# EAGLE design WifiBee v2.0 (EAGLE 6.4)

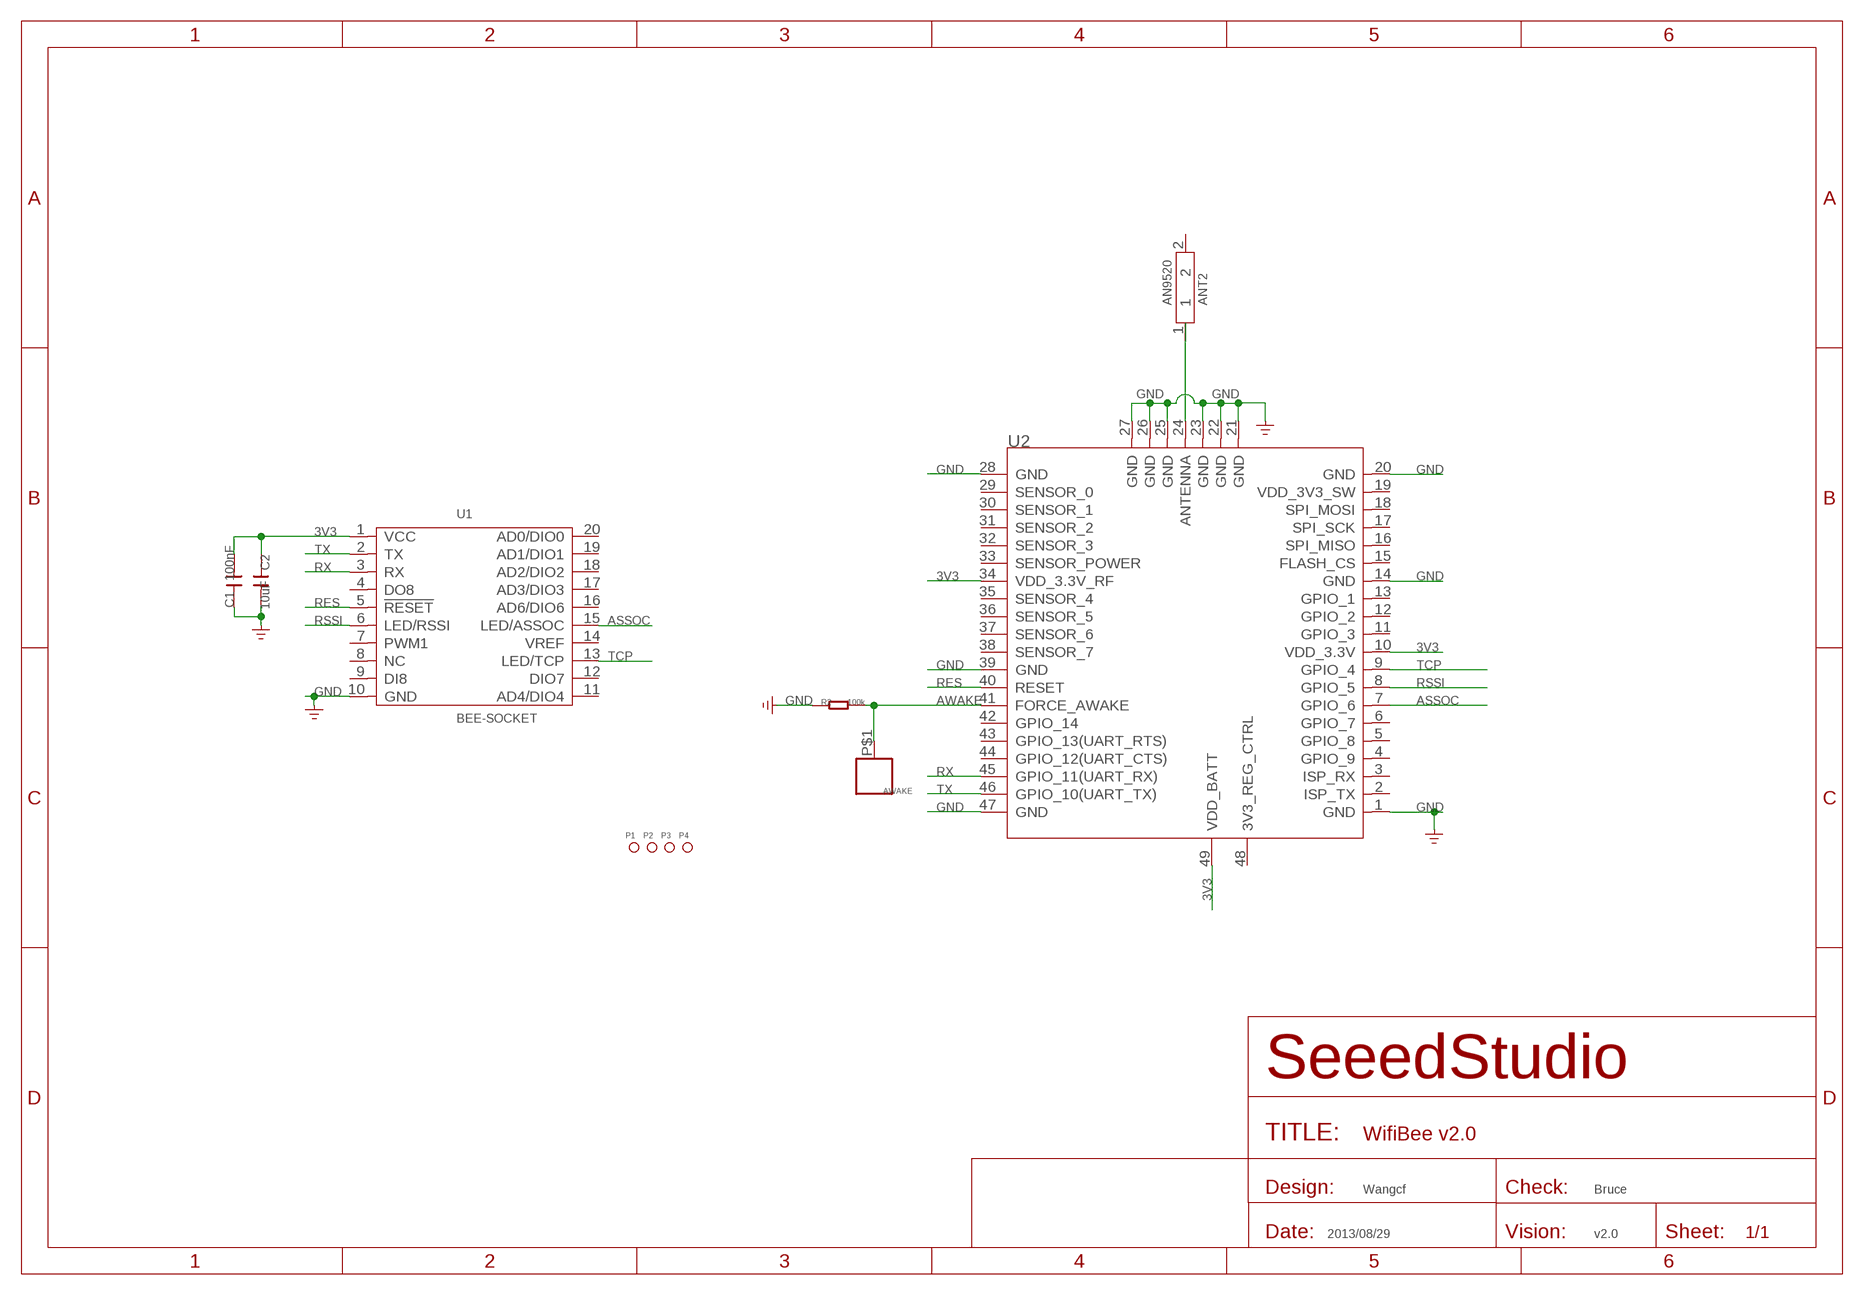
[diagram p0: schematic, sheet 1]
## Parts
ANT2  AN9520  ANTENNA-CERAMICS'AN9520'  [2P-9.5X2.1X1MM]
AWAKE  PAD'65MIL'  [1P-SMD-1.65MM]
C1  100nF  C-0603  [C0603]
C2  10uF  C-0805  [C0805]
P1  PAD-MARK  [ROUND-MARK-1.0]
P2  PAD-MARK  [ROUND-MARK-1.0]
P3  PAD-MARK  [ROUND-MARK-1.0]
P4  PAD-MARK  [ROUND-MARK-1.0]
R2  100k  R-0603  [R0603]
U1  BEE-SOCKET  [20P-DIP-2.0-PRO/NO-SILK]
U2  WIFI-RN-171  [49P-1.27-26.67X17.78]

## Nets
3V3: C1.2 C2.1 U1.1(VCC) U2.10(VDD_3.3V) U2.34(VDD_3.3V_RF) U2.49(VDD_BATT)
ASSOC: U1.15(LED/ASSOC) U2.7(GPIO_6)
AWAKE: AWAKE.P$1 R2.1 U2.41(FORCE_AWAKE)
GND: C1.1 C2.2 R2.2 U1.10(GND) U2.1(GND) U2.14(GND) U2.20(GND) U2.21(GND) U2.22(GND) U2.23(GND) U2.25(GND) U2.26(GND) U2.27(GND) U2.28(GND) U2.39(GND) U2.47(GND)
N$1: ANT2.1 U2.24(ANTENNA)
RES: U1.5(!RESET) U2.40(RESET)
RSSI: U1.6(LED/RSSI) U2.8(GPIO_5)
RX: U1.3(RX) U2.45(GPIO_11(UART_RX))
TCP: U1.13(LED/TCP) U2.9(GPIO_4)
TX: U1.2(TX) U2.46(GPIO_10(UART_TX))
Unconnected: ANT2.2 U1.4(DO8) U1.7(PWM1) U1.8(NC) U1.9(DI8) U1.11(AD4/DIO4) U1.12(DIO7) U1.14(VREF) U1.16(AD6/DIO6) U1.17(AD3/DIO3) U1.18(AD2/DIO2) U1.19(AD1/DIO1) U1.20(AD0/DIO0) U2.2(ISP_TX) U2.3(ISP_RX) U2.4(GPIO_9) U2.5(GPIO_8) U2.6(GPIO_7) U2.11(GPIO_3) U2.12(GPIO_2) U2.13(GPIO_1) U2.15(FLASH_CS) U2.16(SPI_MISO) U2.17(SPI_SCK) U2.18(SPI_MOSI) U2.19(VDD_3V3_SW) U2.29(SENSOR_0) U2.30(SENSOR_1) U2.31(SENSOR_2) U2.32(SENSOR_3) U2.33(SENSOR_POWER) U2.35(SENSOR_4) U2.36(SENSOR_5) U2.37(SENSOR_6) U2.38(SENSOR_7) U2.42(GPIO_14) U2.43(GPIO_13(UART_RTS)) U2.44(GPIO_12(UART_CTS)) U2.48(3V3_REG_CTRL)

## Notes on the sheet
- Wangcf | Bruce
- 2013/08/29 | v2.0

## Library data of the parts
ANT2 = Connector :ANTENNA-CERAMICS: Multilayer Chip Antenna for
AWAKE = Discrete:PAD
C1 C2 = Discrete:C*: Ceramic Capacitors
P1-P4 = Discrete:PAD-MARK; PARTNO: DNP
R2 = Discrete:R*
U1 = moudle:BEE-SOCKET
U2 = moudle:WIFI-RN-171: WIFLY GSX 802.11 b/g wireless LAN Module

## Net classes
0 default: width 0.003 mm, drill 0.254 mm, clearance 0.152 mm

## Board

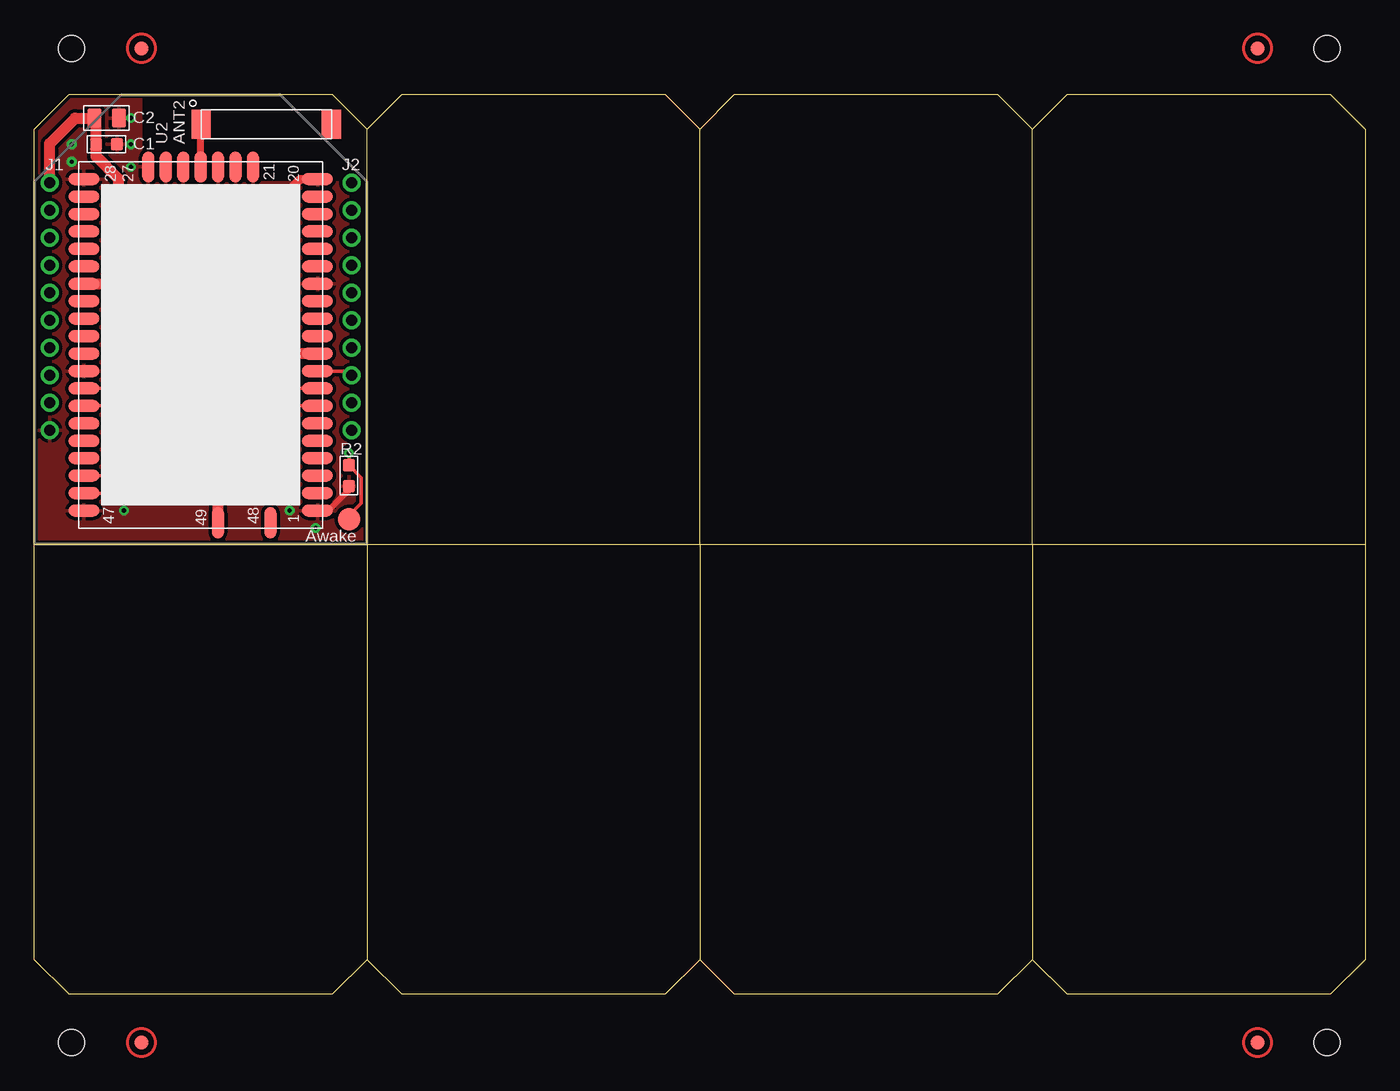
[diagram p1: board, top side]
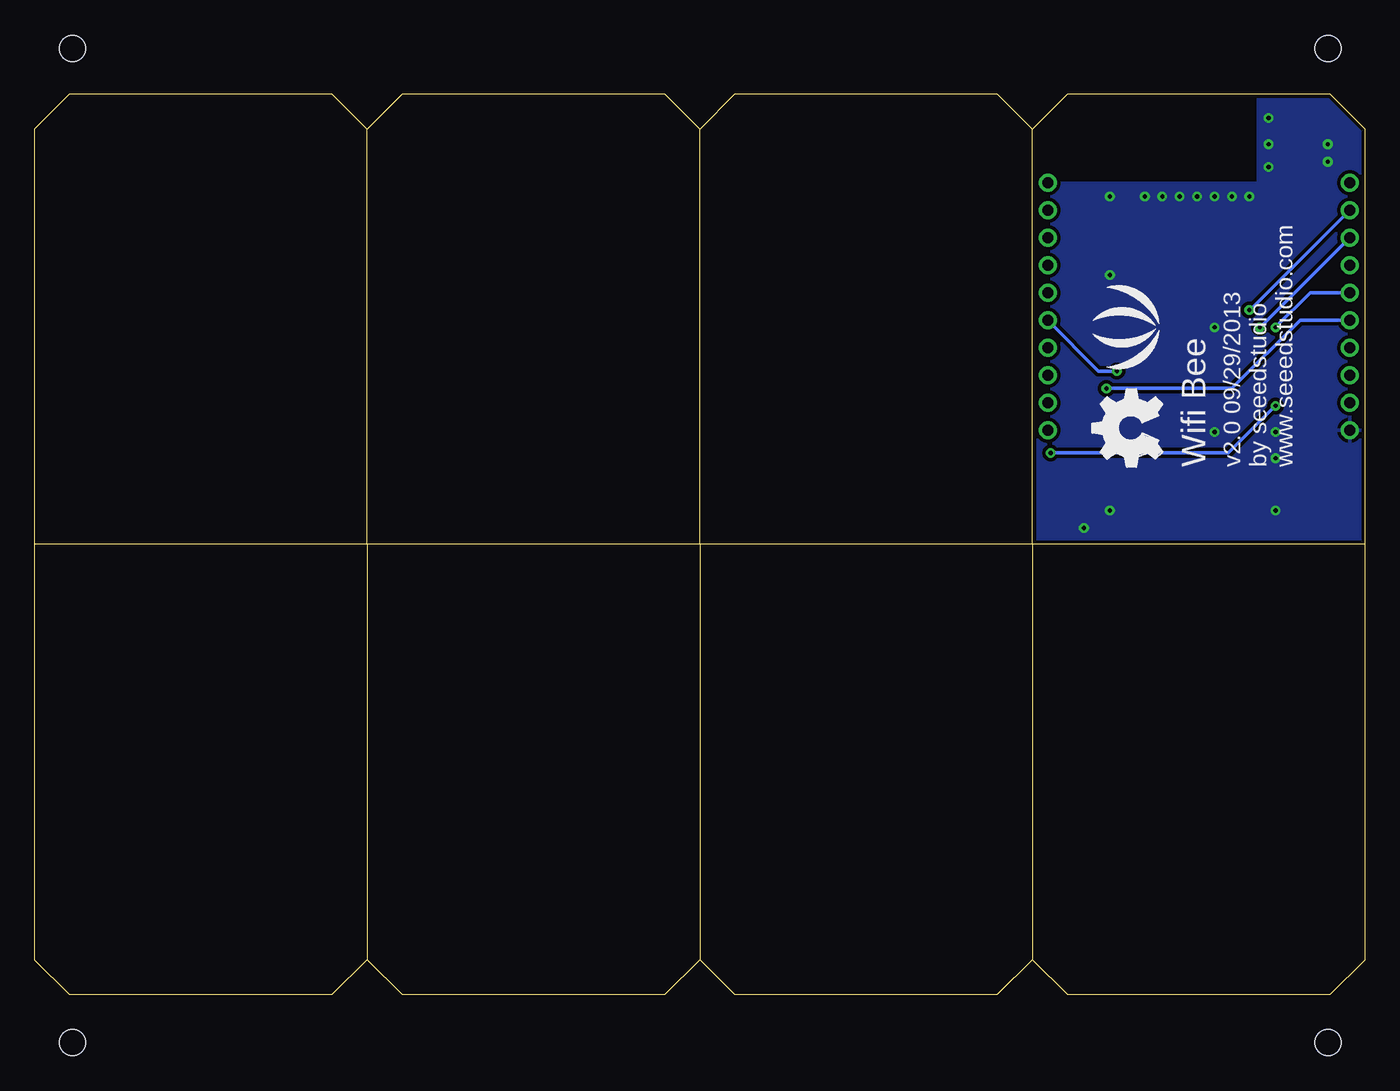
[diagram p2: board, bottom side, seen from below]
Size 96.93 x 65.53 mm. Coordinates in mm from the lower left corner, seen from the top.
Outline: 0,32.77 0,62.99 2.54,65.53 21.69,65.53 24.23,62.99
Outline: 24.23,32.77 24.23,62.99
Outline: 24.23,62.99 26.77,65.53 45.92,65.53 48.46,62.99
Outline: 48.46,32.77 48.46,62.99
Outline: 48.46,62.99 51,65.53 70.15,65.53 72.69,62.99
Outline: 72.69,32.77 72.69,62.99
Outline: 72.69,62.99 75.23,65.53 94.39,65.53 96.93,62.99 96.93,32.77
Outline: 96.93,32.77 96.93,2.54 94.39,0 75.23,0 72.69,2.54
Outline: 72.69,32.77 96.93,32.77
Outline: 72.69,32.77 72.69,2.54
Outline: 72.69,2.54 70.15,0 51,0 48.46,2.54
Outline: 48.46,32.77 72.69,32.77
Outline: 48.46,32.77 48.46,2.54
Outline: 48.46,2.54 45.92,0 26.77,0 24.23,2.54
Outline: 24.23,32.77 48.46,32.77
Outline: 24.23,32.77 24.23,2.54
Outline: 24.23,2.54 21.69,0 2.54,0 0,2.54 0,32.77
Outline: 0,32.77 24.23,32.77
Copper layers (1*16): Top 0.035mm / dielectric 1.5mm / Bottom 0.035mm
Design rules "default *": minimum track width 6mil, minimum drill 12mil, track to track 6mil, track to pad 6mil, pad to pad 6mil, via to via 6mil, smd to smd 0mil, copper to edge 10mil, drill to drill 12mil, minimum pad ring 10mil, minimum via ring 8mil, stop-mask expansion 4mil, vias tented up to drill 25mil, thermal gap 10mil
Holes 1.91 mm at 2.72,-3.51 94.16,-3.51 2.72,68.88 94.16,68.88
tRestrict: area 8.8,59.9 to 9.1,60.6; area 10.1,59.9 to 10.3,60.6; area 13.9,59.9 to 14.1,60.6; area 15.2,59.9 to 15.4,60.6; 4 lines

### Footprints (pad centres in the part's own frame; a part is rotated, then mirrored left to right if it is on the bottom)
2P-9.5X2.1X1MM = smd 1.4 x 2.1: 1 -4.75,0; 2 4.75,0
1P-SMD-1.65MM = smd 1.651 x 1.651: P$1 0,0
C0603 = smd 0.889 x 0.889: 1 -0.762,0; 2 0.762,0
C0805 = smd 1.016 x 1.397: 1 -0.889,0; 2 0.889,0
ROUND-MARK-1.0 = smd 1.016 x 1.016: P$1 0,0
R0603 = smd 0.889 x 0.889: 1 -0.762,0; 2 0.762,0
20P-DIP-2.0-PRO/NO-SILK = drill 0.8 pad 1.27: 1 -11.127,9.889; 2 -11.127,7.889; 3 -11.127,5.889; 4 -11.127,3.889; 5 -11.127,1.889; 6 -11.127,-0.111; 7 -11.127,-2.111; 8 -11.127,-4.111; 9 -11.127,-6.111; 10 -11.127,-8.111; 11 10.873,-8.111; 12 10.873,-6.111; 13 10.873,-4.111; 14 10.873,-2.111; 15 10.873,-0.111; 16 10.873,1.889; 17 10.873,3.889; 18 10.873,5.889; 19 10.873,7.889; 20 10.873,9.889
49P-1.27-26.67X17.78 = smd 0.889 x 2.286: 1 12.065,8.509; 2 10.795,8.509; 3 9.525,8.509; 4 8.255,8.509; 5 6.985,8.509; 6 5.715,8.509; 7 4.445,8.509; 8 3.175,8.509; 9 1.905,8.509; 10 0.635,8.509; 11 -0.635,8.509; 12 -1.905,8.509; 13 -3.175,8.509; 14 -4.445,8.509; 15 -5.715,8.509; 16 -6.985,8.509; 17 -8.255,8.509; 18 -9.525,8.509; 19 -10.795,8.509; 20 -12.065,8.509; 28 -12.065,-8.509; 29 -10.795,-8.509; 30 -9.525,-8.509; 31 -8.255,-8.509; 32 -6.985,-8.509; 33 -5.715,-8.509; 34 -4.445,-8.509; 35 -3.175,-8.509; 36 -1.905,-8.509; 37 -0.635,-8.509; 38 0.635,-8.509; 39 1.905,-8.509; 40 3.175,-8.509; 41 4.445,-8.509; 42 5.715,-8.509; 43 6.985,-8.509; 44 8.255,-8.509; 45 9.525,-8.509; 46 10.795,-8.509; 47 12.065,-8.509 | smd 2.286 x 0.889: 21 -12.954,3.81; 22 -12.954,2.54; 23 -12.954,1.27; 24 -12.954,0; 25 -12.954,-1.27; 26 -12.954,-2.54; 27 -12.954,-3.81; 48 12.954,5.08; 49 12.954,1.27

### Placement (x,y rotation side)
ANT2  16.89,63.36 0 top
AWAKE  22.91,34.59 0 top
C1  5.26,61.9 180 top
C2  5.26,63.8 0 top
P1  not placed on the board
P2  not placed on the board
P3  not placed on the board
P4  not placed on the board
R2  22.91,37.77 270 top
U1  12.24,49.2 0 top
U2  12.12,47.29 270 top
U$1  [LOGO_SILK]  16.69,48.56 90 bottom
U$2  [OSHW_FILLX200_NOTEXT]  14.78,38.4 90 bottom

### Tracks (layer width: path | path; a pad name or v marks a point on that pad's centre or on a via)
3V3
  Top 0.813: U1.1 1.12,61.95 2.97,63.8 C2.1 4.5,63.68 C1.2 4.5,61.01 6.15,59.36 6.15,52.37 | U2.10 14.53,46.66 13.77,46.66 | U2.34 5.51,51.74 | 5.51,51.74 6.78,51.74 | 6.78,51.74 10.46,51.74 13.39,48.82 13.39,47.04 | 6.15,52.37 5.51,51.74 | 6.15,52.37 6.78,51.74 | U2.49 13.39,46.28 | 13.39,46.28 13.39,47.04 | 13.77,46.66 13.39,47.04 | 13.77,46.66 13.39,46.28
ASSOC  (via drill 0.3 pad 0.64)
  Top 0.254: U2.7 18.59,42.85 18.08,43.36 v18.08,45.39
  Bottom 0.254: v18.08,45.39 19.42,45.39 U1.15
AWAKE  (via drill 0.3 pad 0.64)
  Top 0.254: v6.53,42.85 U2.41 3.48,42.85 | v22.91,39.42 R2.1 23.81,37.63 23.81,35.75 22.91,34.85 AWAKE.P$1
  Bottom 0.254: v6.53,42.85 9.96,39.42 v22.91,39.42
GND  (via drill 0.3, 0.3 pad 0.64)
  Top 0.406: R2.2 22.91,36.75 21.39,35.23 20.5,35.23
  Top 0.61: U2.20 19.35,59.36 18.59,58.6 v18.59,58.09
  other vias: 6.53,40.94 7.04,63.8 7.04,61.9 8.43,58.09 9.7,58.09 10.97,58.09 13.51,58.09 14.78,58.09 16.05,58.09 18.59,52.37 18.59,35.23 6.53,35.23 6.53,39.04 12.24,58.09 20.5,33.96 2.72,61.9 2.72,60.63 7.04,60.25 10.97,40.94 10.97,48.56
  pour Bottom (isolate 0.254): 7.8,65.65 -0.08,65.58 -0.08,32.69 24.31,32.69 24.43,59.11 7.8,59.11
  pour Top (isolate 0.254): 7.8,65.65 -0.08,65.58 -0.08,32.69 24.31,32.69 24.43,59.11 7.8,59.11
N$1
  Top 0.508: U2.24 12.12,63.33 ANT2.1
RES  (via drill 0.3 pad 0.64)
  Top 0.254: v6.53,48.56 6.53,44.75 5.89,44.12 U2.40
  Bottom 0.254: U1.5 4,51.09 v6.53,48.56
RSSI  (via drill 0.3 pad 0.64)
  Top 0.254: v18.85,44.12 U2.8
  Bottom 0.254: U1.6 4.73,49.09 9.7,44.12 v18.85,44.12
RX  (via drill 0.3 pad 0.64)
  Top 0.254: U2.45 6.4,37.77 7.67,39.04 v7.67,48.56
  Bottom 0.254: v7.67,48.56 7.67,48.53 U1.3
TCP
  Top 0.254: U2.9 22.81,45.39 U1.13
TX  (via drill 0.3 pad 0.64)
  Top 0.254: U2.46 6.65,36.5 8.43,38.28 v8.43,49.83
  Bottom 0.254: v8.43,49.83 8.43,49.77 U1.2

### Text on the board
tPlace: J1
bPlace: www.seeedstudio.com | by seeedstudio | v2.0 09/29/2013 | Wifi Bee
tNames: J2 | Awake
